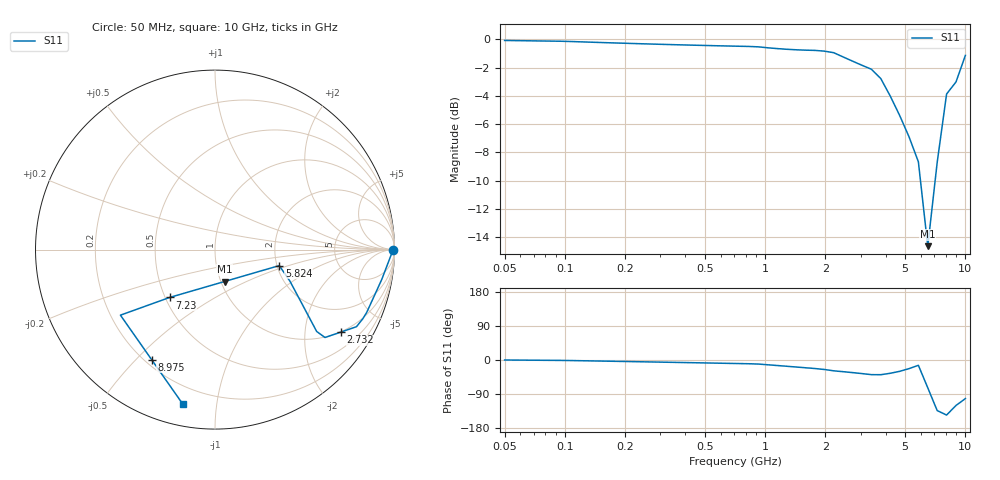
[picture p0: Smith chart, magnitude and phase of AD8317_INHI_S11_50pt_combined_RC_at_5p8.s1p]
! AD8317 INHI/INLO input model, 0.05-10 GHz
! Sources: AD8317 Rev.D pp.3-4 impedance table + p.9 Figure 15 approximation
! INLO is RF common (AC-coupled to ground), modeled implicitly in single-ended S11 at INHI.
# GHZ S RI R 50
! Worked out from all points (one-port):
!   50 points, 50 MHz to 10 GHz, reference 50 ohm
!   lowest |S11| = -14.6 dB at 6.489 GHz (marker M1), VSWR 1.46, Z = 52 - j19.1 ohm
!   |S11| at or under -10 dB: 5.973 GHz to 7.068 GHz (1.095 GHz wide, 16.8 % of centre)
!   S11 on the Smith chart (normalised r, x): 50 MHz: open; 2.732 GHz: 0.99, -3.06; 5.824 GHz: 2.06, -0.42; 7.23 GHz: 0.53, -0.33; 8.975 GHz: 0.23, -0.56; 10 GHz: 0.11, -0.81
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0.05  0.992 0
0.09566  0.9854 -0.0187
0.106583  0.9834 -0.0243
0.203914  0.9667 -0.0678
0.390127  0.9501 -0.1114
0.746388  0.9334 -0.1549
0.83162  0.9307 -0.1622
0.926583  0.925 -0.1753
1.150281  0.8985 -0.2335
1.281634  0.8852 -0.2626
1.427985  0.8719 -0.2916
1.591049  0.8586 -0.3207
1.772733  0.8453 -0.3498
1.975164  0.824 -0.3846
2.20071  0.7884 -0.4295
2.732011  0.7007 -0.4597
3.043983  0.6569 -0.4747
3.39158  0.613 -0.4898
3.778869  0.5666 -0.4562
4.210383  0.5169 -0.3627
4.691173  0.4672 -0.2692
5.226864  0.4175 -0.1757
5.823727  0.3581 -0.0891
6.488747  0.0529 -0.1778
7.229706  -0.2522 -0.2665
8.055276  -0.5269 -0.3653
8.975119  -0.3534 -0.6126
10  -0.18 -0.86
